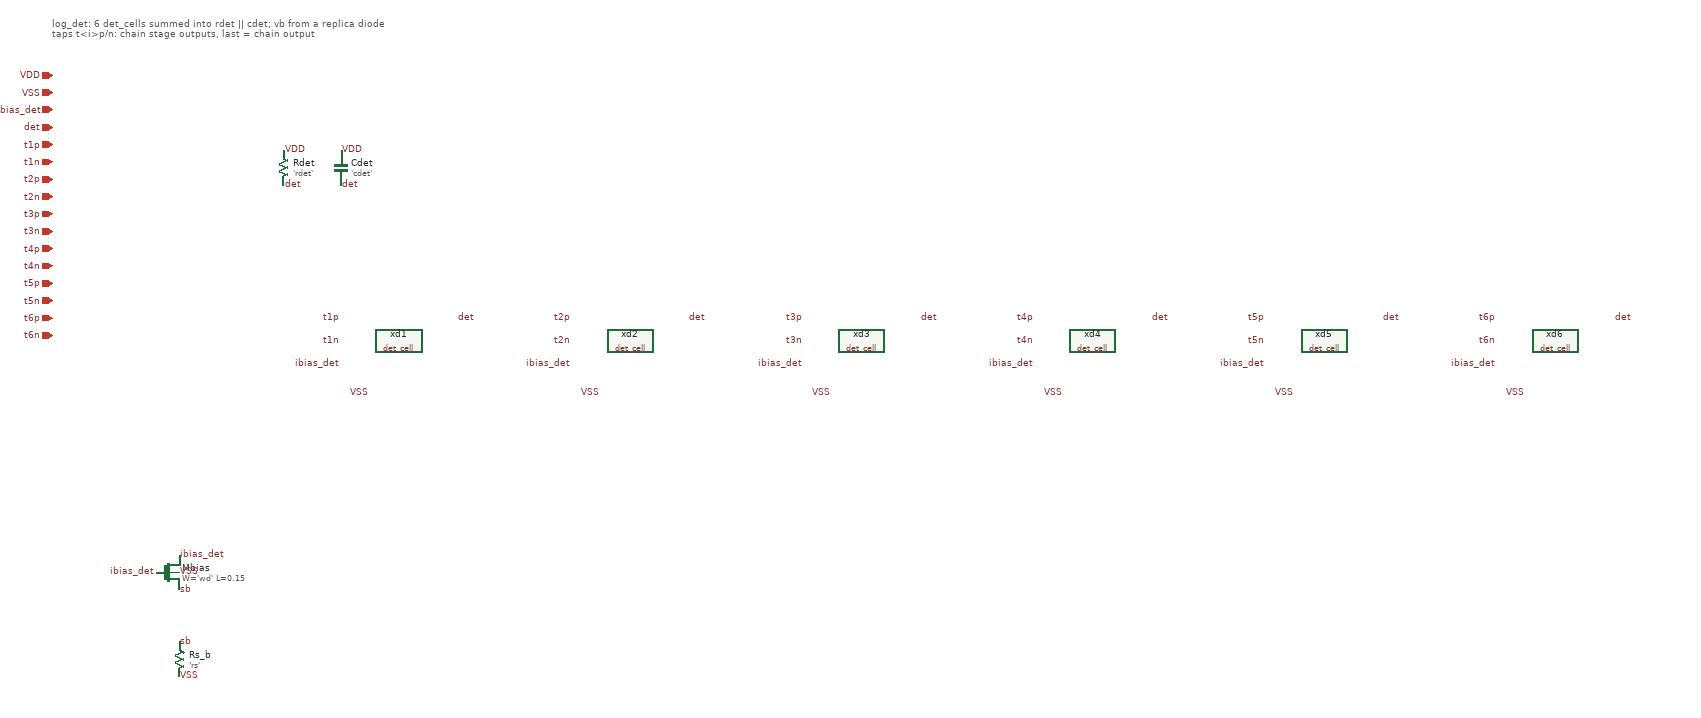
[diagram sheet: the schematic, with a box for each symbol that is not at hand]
v {xschem version=3.4.5 file_version=1.2
}
G {}
K {}
V {}
S {}
E {}
T {log_det: 6 det_cells summed into rdet || cdet; vb from a replica diode
taps t<i>p/n: chain stage outputs, last = chain output} -600 -760 0 0 0.4 0.4 {}
C {devices/iopin.sym} -600 -660 0 0 {name=p1
lab=VDD}
C {devices/iopin.sym} -600 -630 0 0 {name=p2
lab=VSS}
C {devices/iopin.sym} -600 -600 0 0 {name=p3
lab=ibias_det}
C {devices/iopin.sym} -600 -570 0 0 {name=p4
lab=det}
C {devices/iopin.sym} -600 -540 0 0 {name=p5
lab=t1p}
C {devices/iopin.sym} -600 -510 0 0 {name=p6
lab=t1n}
C {devices/iopin.sym} -600 -480 0 0 {name=p7
lab=t2p}
C {devices/iopin.sym} -600 -450 0 0 {name=p8
lab=t2n}
C {devices/iopin.sym} -600 -420 0 0 {name=p9
lab=t3p}
C {devices/iopin.sym} -600 -390 0 0 {name=p10
lab=t3n}
C {devices/iopin.sym} -600 -360 0 0 {name=p11
lab=t4p}
C {devices/iopin.sym} -600 -330 0 0 {name=p12
lab=t4n}
C {devices/iopin.sym} -600 -300 0 0 {name=p13
lab=t5p}
C {devices/iopin.sym} -600 -270 0 0 {name=p14
lab=t5n}
C {devices/iopin.sym} -600 -240 0 0 {name=p15
lab=t6p}
C {devices/iopin.sym} -600 -210 0 0 {name=p16
lab=t6n}
C {sky130_fd_pr/nfet_01v8.sym} -400 200 0 0 {name=Mbias
nf=1
mult=1
ad="'int((nf+1)/2) * W/nf * 0.29'"
pd="'2*int((nf+1)/2) * (W/nf + 0.29)'"
as="'int((nf+2)/2) * W/nf * 0.29'"
ps="'2*int((nf+2)/2) * (W/nf + 0.29)'"
nrd="'0.29 / W'"
nrs="'0.29 / W'"
sa=0
sb=0
sd=0
L=0.15
W='wd'
model=nfet_01v8
spiceprefix=X}
C {devices/lab_pin.sym} -380 170 0 1 {name=p17
sig_type=std_logic
lab=ibias_det}
C {devices/lab_pin.sym} -420 200 0 0 {name=p18
sig_type=std_logic
lab=ibias_det}
C {devices/lab_pin.sym} -380 230 0 1 {name=p19
sig_type=std_logic
lab=sb}
C {devices/lab_pin.sym} -380 200 0 1 {name=p20
sig_type=std_logic
lab=VSS}
C {devices/res.sym} -380 350 0 0 {name=Rs_b
value='rs'
m=1}
C {devices/lab_pin.sym} -380 320 0 1 {name=p21
sig_type=std_logic
lab=sb}
C {devices/lab_pin.sym} -380 380 0 1 {name=p22
sig_type=std_logic
lab=VSS}
C {devices/res.sym} -200 -500 0 0 {name=Rdet
value='rdet'
m=1}
C {devices/lab_pin.sym} -200 -530 0 1 {name=p23
sig_type=std_logic
lab=VDD}
C {devices/lab_pin.sym} -200 -470 0 1 {name=p24
sig_type=std_logic
lab=det}
C {devices/capa.sym} -100 -500 0 0 {name=Cdet
value='cdet'
m=1}
C {devices/lab_pin.sym} -100 -530 0 1 {name=p25
sig_type=std_logic
lab=VDD}
C {devices/lab_pin.sym} -100 -470 0 1 {name=p26
sig_type=std_logic
lab=det}
C {det_cell.sym} 0 -200 0 0 {name=xd1
wd='wd'
rs='rs'
cc='cc'
rb='rb'}
C {devices/lab_pin.sym} -100 -240 0 0 {name=p27
sig_type=std_logic
lab=t1p}
C {devices/lab_pin.sym} -100 -200 0 0 {name=p28
sig_type=std_logic
lab=t1n}
C {devices/lab_pin.sym} -100 -160 0 0 {name=p29
sig_type=std_logic
lab=ibias_det}
C {devices/lab_pin.sym} 100 -240 0 1 {name=p30
sig_type=std_logic
lab=det}
C {devices/lab_pin.sym} -50 -110 0 0 {name=p31
sig_type=std_logic
lab=VSS}
C {det_cell.sym} 400 -200 0 0 {name=xd2
wd='wd'
rs='rs'
cc='cc'
rb='rb'}
C {devices/lab_pin.sym} 300 -240 0 0 {name=p32
sig_type=std_logic
lab=t2p}
C {devices/lab_pin.sym} 300 -200 0 0 {name=p33
sig_type=std_logic
lab=t2n}
C {devices/lab_pin.sym} 300 -160 0 0 {name=p34
sig_type=std_logic
lab=ibias_det}
C {devices/lab_pin.sym} 500 -240 0 1 {name=p35
sig_type=std_logic
lab=det}
C {devices/lab_pin.sym} 350 -110 0 0 {name=p36
sig_type=std_logic
lab=VSS}
C {det_cell.sym} 800 -200 0 0 {name=xd3
wd='wd'
rs='rs'
cc='cc'
rb='rb'}
C {devices/lab_pin.sym} 700 -240 0 0 {name=p37
sig_type=std_logic
lab=t3p}
C {devices/lab_pin.sym} 700 -200 0 0 {name=p38
sig_type=std_logic
lab=t3n}
C {devices/lab_pin.sym} 700 -160 0 0 {name=p39
sig_type=std_logic
lab=ibias_det}
C {devices/lab_pin.sym} 900 -240 0 1 {name=p40
sig_type=std_logic
lab=det}
C {devices/lab_pin.sym} 750 -110 0 0 {name=p41
sig_type=std_logic
lab=VSS}
C {det_cell.sym} 1200 -200 0 0 {name=xd4
wd='wd'
rs='rs'
cc='cc'
rb='rb'}
C {devices/lab_pin.sym} 1100 -240 0 0 {name=p42
sig_type=std_logic
lab=t4p}
C {devices/lab_pin.sym} 1100 -200 0 0 {name=p43
sig_type=std_logic
lab=t4n}
C {devices/lab_pin.sym} 1100 -160 0 0 {name=p44
sig_type=std_logic
lab=ibias_det}
C {devices/lab_pin.sym} 1300 -240 0 1 {name=p45
sig_type=std_logic
lab=det}
C {devices/lab_pin.sym} 1150 -110 0 0 {name=p46
sig_type=std_logic
lab=VSS}
C {det_cell.sym} 1600 -200 0 0 {name=xd5
wd='wd'
rs='rs'
cc='cc'
rb='rb'}
C {devices/lab_pin.sym} 1500 -240 0 0 {name=p47
sig_type=std_logic
lab=t5p}
C {devices/lab_pin.sym} 1500 -200 0 0 {name=p48
sig_type=std_logic
lab=t5n}
C {devices/lab_pin.sym} 1500 -160 0 0 {name=p49
sig_type=std_logic
lab=ibias_det}
C {devices/lab_pin.sym} 1700 -240 0 1 {name=p50
sig_type=std_logic
lab=det}
C {devices/lab_pin.sym} 1550 -110 0 0 {name=p51
sig_type=std_logic
lab=VSS}
C {det_cell.sym} 2000 -200 0 0 {name=xd6
wd='wd'
rs='rs'
cc='cc'
rb='rb'}
C {devices/lab_pin.sym} 1900 -240 0 0 {name=p52
sig_type=std_logic
lab=t6p}
C {devices/lab_pin.sym} 1900 -200 0 0 {name=p53
sig_type=std_logic
lab=t6n}
C {devices/lab_pin.sym} 1900 -160 0 0 {name=p54
sig_type=std_logic
lab=ibias_det}
C {devices/lab_pin.sym} 2100 -240 0 1 {name=p55
sig_type=std_logic
lab=det}
C {devices/lab_pin.sym} 1950 -110 0 0 {name=p56
sig_type=std_logic
lab=VSS}
